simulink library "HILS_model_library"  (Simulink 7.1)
undefined symbols (not defined in the file or in its folder): hilsmdl
libraries: simulink x47, simulink_extras x9, HILS_model_library x3
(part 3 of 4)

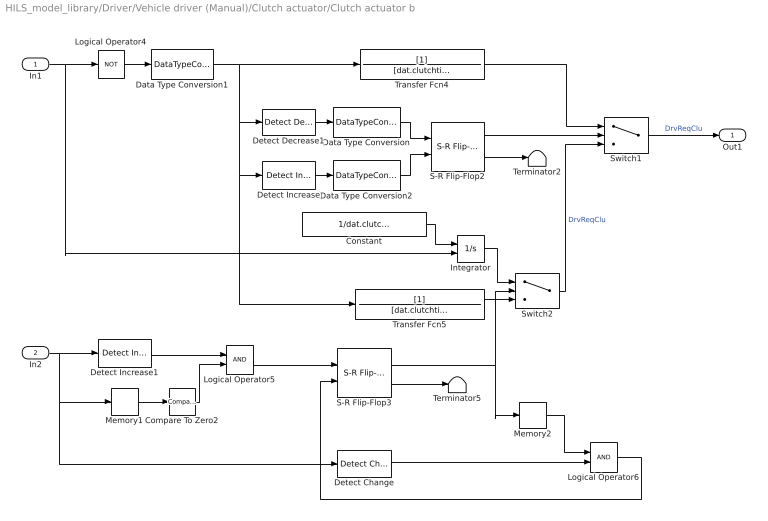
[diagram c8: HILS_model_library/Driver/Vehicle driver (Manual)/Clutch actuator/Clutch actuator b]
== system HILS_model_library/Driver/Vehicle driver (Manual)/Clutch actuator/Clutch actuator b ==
  In1 : Inport
  In2 : Inport  Port=2
  Compare To Zero2 : simulink/Logic and Bit Operations/Compare To Zero  SystemSampleTime=-1  relop===  LogicOutDataTypeMode=boolean
  Constant : Constant  Value=1/dat.clutchtime.driveaway.value
  Data Type Conversion : DataTypeConversion
  Data Type Conversion1 : DataTypeConversion
  Data Type Conversion2 : DataTypeConversion
  Detect Change : simulink/Logic and Bit Operations/Detect Change  SystemSampleTime=-1  vinit=0
  Detect Decrease1 : simulink/Logic and Bit Operations/Detect Decrease  SystemSampleTime=-1  vinit=0.0
  Detect Increase : simulink/Logic and Bit Operations/Detect Increase  SystemSampleTime=-1  vinit=0.0
  Detect Increase1 : simulink/Logic and Bit Operations/Detect Increase  SystemSampleTime=-1  vinit=0.0
  Integrator : Integrator  ExternalReset=either  LimitOutput=on  UpperSaturationLimit=1  LowerSaturationLimit=0
  Logical Operator4 : Logic  Operator=NOT  AllPortsSameDT=off  OutDataTypeMode=boolean  OutDataTypeStr=boolean
  Logical Operator5 : Logic  AllPortsSameDT=off  OutDataTypeMode=boolean  OutDataTypeStr=boolean
  Logical Operator6 : Logic  AllPortsSameDT=off  OutDataTypeMode=boolean  OutDataTypeStr=boolean
  Memory1 : Memory
  Memory2 : Memory
  S-R Flip-Flop2 : simulink_extras/Flip Flops/S-R Flip-Flop  SystemSampleTime=-1  initial_condition=0
  S-R Flip-Flop3 : simulink_extras/Flip Flops/S-R Flip-Flop  SystemSampleTime=-1  initial_condition=0
  Switch1 : Switch  Threshold=1
  Switch2 : Switch  Threshold=1
  Terminator2 : Terminator
  Terminator5 : Terminator
  Transfer Fcn4 : TransferFcn  Denominator=[dat.clutchtime.open.value 1]
  Transfer Fcn5 : TransferFcn  Denominator=[dat.clutchtime.close.value 1]
  Out1 : Outport
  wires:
  Constant/1 -> Integrator/1
  In2/1 -> Memory1/1, Detect Change/1, Detect Increase1/1
  Data Type Conversion1/1 -> Transfer Fcn5/1, Detect Increase/1, Detect Decrease1/1, Transfer Fcn4/1
  Detect Increase/1 -> Data Type Conversion2/1
  Switch1/1 -> Out1/1  "DrvReqClu"
  Transfer Fcn4/1 -> Switch1/1
  In1/1 -> Logical Operator4/1, Integrator/2
  Logical Operator4/1 -> Data Type Conversion1/1
  Detect Decrease1/1 -> Data Type Conversion/1
  Transfer Fcn5/1 -> Switch2/3
  S-R Flip-Flop3/2 -> Terminator5/1
  S-R Flip-Flop3/1 -> Memory2/1, Switch2/2
  Switch2/1 -> Switch1/3  "DrvReqClu"
  S-R Flip-Flop2/1 -> Switch1/2
  S-R Flip-Flop2/2 -> Terminator2/1
  Integrator/1 -> Switch2/1
  Logical Operator5/1 -> S-R Flip-Flop3/1
  Logical Operator6/1 -> S-R Flip-Flop3/2
  Memory2/1 -> Logical Operator6/1
  Detect Increase1/1 -> Logical Operator5/1
  Detect Change/1 -> Logical Operator6/2
  Compare To Zero2/1 -> Logical Operator5/2
  Memory1/1 -> Compare To Zero2/1
  Data Type Conversion/1 -> S-R Flip-Flop2/1
  Data Type Conversion2/1 -> S-R Flip-Flop2/2

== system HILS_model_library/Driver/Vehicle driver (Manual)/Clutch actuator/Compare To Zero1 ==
  u : Inport
  Compare : RelationalOperator  Operator===  LogicOutDataTypeMode=Specify via dialog  LogicDataType=fixdt(0, 8)  OutDataTypeStr=fixdt(0, 8)
  Ground : Ground  DisableCoverage=on
  Signal Specification : SignalSpecification  DisableCoverage=on  Dimensions=1
  y : Outport
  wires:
  Compare/1 -> y/1
  Ground/1 -> Signal Specification/1
  u/1 -> Compare/1
  Signal Specification/1 -> Compare/2

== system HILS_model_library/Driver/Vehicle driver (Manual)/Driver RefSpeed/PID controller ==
  PI reset : Inport
  PI input : Inport  Port=2
  Add : Sum  Inputs=+++
  Derivative : Derivative
  Integrator : Integrator  ExternalReset=rising  UpperSaturationLimit=30  LowerSaturationLimit=0
  Kd : Gain  Gain=dat.controller.d.value
  Ki : Gain  Gain=dat.controller.i.value
  Kp : Gain  Gain=dat.controller.p.value
  Kw : Gain  Orientation=left  Gain=dat.controller.k.value
  Saturation : Saturate  UpperLimit=1  LowerLimit=-1
  Sum1 : Sum  Inputs=|++
  Sum2 : Sum  Orientation=left  Inputs=-+|
  PI output : Outport
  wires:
  Derivative/1 -> Add/2
  Kd/1 -> Derivative/1
  PI input/1 -> Kd/1, Kp/1, Ki/1
  Integrator/1 -> Add/3
  Add/1 -> Saturation/1, Sum2/1
  Saturation/1 -> PI output/1, Sum2/2
  PI reset/1 -> Integrator/2
  Kp/1 -> Add/1
  Ki/1 -> Sum1/1
  Sum1/1 -> Integrator/1
  Sum2/1 -> Kw/1
  Kw/1 -> Sum1/2

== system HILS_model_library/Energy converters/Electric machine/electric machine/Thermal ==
  Total power loss : Inport
  Massflow cooling fluid : Inport  Port=2
  Bus Creator2 : BusCreator  Inputs=2
  Cooling2 : Subsystem
  c2 : Constant  Value=dat.coolingFluid.flowTemp.value
  Machine temperature[K] : Outport
  Fluid outlet temperature[K] : Outport  Port=2
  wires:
  Bus Creator2/1 -> Cooling2/2(cooling inlet)
  c2/1 -> Bus Creator2/2  "temperature [K]"
  Massflow cooling fluid/1 -> Bus Creator2/1  "mass flow [kg/s]"
  Cooling2/1(internal temperature) -> Machine temperature[K]/1  "ElecMac_tAct_K"
  Total power loss/1 -> Cooling2/1(power loss)
  Cooling2/2(fluid outlet temperature) -> Fluid outlet temperature[K]/1  "ElecMac_tActCoolingOut_K"

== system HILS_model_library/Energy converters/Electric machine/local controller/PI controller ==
  RefSpeed : Inport
  ActSpeed : Inport  Port=2
  Reset : Inport  Port=3
  Gain : Gain  Gain=dat.controller.i.value
  Gain2 : Gain  Gain=dat.controller.p.value
  Integrator : Integrator  ExternalReset=either
  Product : Product
  Sum : Sum  Inputs=|+-
  Sum1 : Sum  Inputs=|++
  Ctrl signal : Outport
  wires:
  Sum1/1 -> Ctrl signal/1
  Reset/1 -> Integrator/2, Product/2
  ActSpeed/1 -> Sum/2
  RefSpeed/1 -> Sum/1
  Product/1 -> Integrator/1
  Gain/1 -> Product/1
  Gain2/1 -> Sum1/2
  Integrator/1 -> Sum1/1
  Sum/1 -> Gain2/1, Gain/1

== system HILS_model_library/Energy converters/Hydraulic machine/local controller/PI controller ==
  Ref : Inport
  Act : Inport  Port=2
  Reset : Inport  Port=3
  Gain : Gain  Gain=dat.controller.i.value
  Gain2 : Gain  Gain=dat.controller.p.value
  Integrator : Integrator  ExternalReset=either
  Sum : Sum  Inputs=|+-
  Sum1 : Sum  Inputs=|++
  Ctrl signal : Outport
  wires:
  Sum/1 -> Gain/1, Gain2/1
  Integrator/1 -> Sum1/1
  Gain2/1 -> Sum1/2
  Gain/1 -> Integrator/1
  Ref/1 -> Sum/1
  Act/1 -> Sum/2
  Reset/1 -> Integrator/2
  Sum1/1 -> Ctrl signal/1

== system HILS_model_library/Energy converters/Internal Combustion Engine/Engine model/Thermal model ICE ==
  Torque ICE : Inport
  Eng speed : Inport  Port=2
  Calc ICE mech. Power : Product
  Compare To fixed temp (1=true) : simulink/Logic and Bit Operations/Compare To Constant  SystemSampleTime=-1  relop=>=  const=dat.cf.fixtemp.value-0.5  LogicOutDataTypeMode=uint8
  Compare To fixed temp (1=true)1 : simulink/Logic and Bit Operations/Compare To Constant  SystemSampleTime=-1  relop=>=  const=dat.oil.fixtemp.value-0.5  LogicOutDataTypeMode=uint8
  Constant : Constant  Value=0
  Integrator1 : Integrator
  Memory : Memory  X0=hilsmdl.init.temp.value
  Memory1 : Memory  X0=hilsmdl.init.temp.value
  MinMax : MinMax  Function=max  Inputs=2
  Switch : Switch  Criteria=u2 > Threshold
  Switch1 : Switch  Criteria=u2 > Threshold
  cooling fluid map : Lookup  InputValues=dat.cf.heatloss.vec  Table=dat.cf.temp.vec  LookUpMeth=Interpolation-Use End Values
  energy loss to cooling and oil [kJ] : Gain  Gain=1/1000
  fixed temp : Constant  Value=dat.cf.fixtemp.value
  fixed temp1 : Constant  Value=dat.oil.fixtemp.value
  oil map : Lookup  InputValues=dat.oil.heatloss.vec  Table=dat.oil.temp.vec  LookUpMeth=Interpolation-Use End Values
  temperature cooling fluid [K] : Outport
  temperature oil [K] : Outport  Port=2
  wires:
  Eng speed/1 -> Calc ICE mech. Power/1
  Torque ICE/1 -> Calc ICE mech. Power/2
  Calc ICE mech. Power/1 -> MinMax/1  "mech. power ICE [W]"
  Integrator1/1 -> energy loss to cooling and oil [kJ]/1
  energy loss to cooling and oil [kJ]/1 -> cooling fluid map/1, oil map/1
  cooling fluid map/1 -> Switch/3
  Memory/1 -> Compare To fixed temp (1=true)/1
  Compare To fixed temp (1=true)/1 -> Switch/2
  fixed temp/1 -> Switch/1
  oil map/1 -> Switch1/3
  Memory1/1 -> Compare To fixed temp (1=true)1/1
  Compare To fixed temp (1=true)1/1 -> Switch1/2
  fixed temp1/1 -> Switch1/1
  Switch1/1 -> temperature oil [K]/1, Memory1/1
  Switch/1 -> temperature cooling fluid [K]/1, Memory/1
  MinMax/1 -> Integrator1/1
  Constant/1 -> MinMax/2

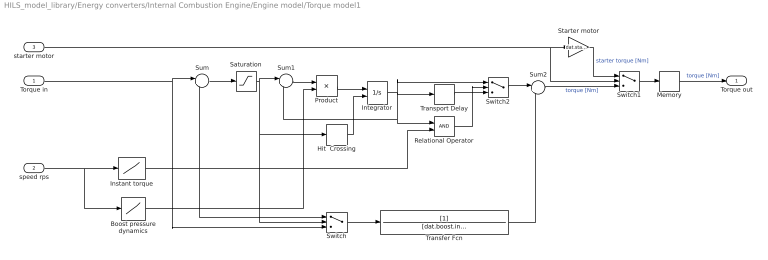
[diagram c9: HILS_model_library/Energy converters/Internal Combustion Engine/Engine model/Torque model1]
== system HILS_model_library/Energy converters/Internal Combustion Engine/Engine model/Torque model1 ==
  Torque in : Inport
  speed rps : Inport  Port=2
  starter motor : Inport  Port=3
  Boost pressure dynamics : Lookup  InputValues=dat.boost.speed.vec  Table=dat.boost.timeconstant.T2.vec  LookUpMeth=Interpolation-Use End Values
  Hit  Crossing : HitCross  HitCrossingDirection=falling
  Instant torque : Lookup  InputValues=dat.boost.speed.vec  Table=dat.boost.insttorque.vec  LookUpMeth=Interpolation-Use End Values
  Integrator : Integrator  ExternalReset=rising
  Memory : Memory
  Product : Product  Inputs=*/
  Relational Operator : RelationalOperator  LogicOutDataTypeMode=boolean  OutDataTypeStr=boolean
  Saturation : Saturate  UpperLimit=inf  LowerLimit=0
  Starter motor : Gain  Gain=dat.startertorque.value
  Sum : Sum  Inputs=|+-
  Sum1 : Sum  Inputs=|+-
  Sum2 : Sum  Inputs=|++
  Switch : Switch  Criteria=u2 > Threshold
  Switch1 : Switch  Threshold=0.5
  Switch2 : Switch  Criteria=u2 > Threshold  Threshold=0.5
  Transfer Fcn : TransferFcn  Denominator=[dat.boost.insttorque.timeconstant.T1.value/3 1]
  Transport Delay : TransportDelay  DelayTime=dat.boost.insttorque.timeconstant.T1.value
  Torque out : Outport
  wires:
  Starter motor/1 -> Switch1/1  "starter torque [Nm]"
  Sum2/1 -> Switch1/3  "torque [Nm]"
  Switch1/1 -> Memory/1
  starter motor/1 -> Starter motor/1, Switch1/2
  Memory/1 -> Torque out/1  "torque [Nm]"
  Hit  Crossing/1 -> Integrator/2
  Switch/1 -> Transfer Fcn/1
  Product/1 -> Integrator/1
  Sum1/1 -> Product/1
  Saturation/1 -> Switch/2, Hit  Crossing/1, Sum1/1
  Torque in/1 -> Switch/3, Sum/1
  Sum/1 -> Saturation/1
  Instant torque/1 -> Switch/1, Relational Operator/2, Sum/2
  Boost pressure dynamics/1 -> Product/2
  speed rps/1 -> Boost pressure dynamics/1, Instant torque/1
  Transfer Fcn/1 -> Sum2/2
  Integrator/1 -> Switch2/1, Transport Delay/1, Relational Operator/1, Sum1/2
  Relational Operator/1 -> Switch2/2
  Transport Delay/1 -> Switch2/3
  Switch2/1 -> Sum2/1

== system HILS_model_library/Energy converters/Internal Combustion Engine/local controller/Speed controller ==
  RefSpeed : Inport
  ActSpeed : Inport  Orientation=up  Port=2
  Reset : Inport  Orientation=up  Port=3
  Gain : Gain  Gain=dat.controller.i.value
  Gain2 : Gain  Gain=dat.controller.p.value
  Integrator : Integrator  ExternalReset=either
  Product : Product
  Saturation : Saturate  UpperLimit=max(dat.maxtorque.torque.vec)-min(dat.friction.friction.vec)  LowerLimit=0
  Sum : Sum  Inputs=|+-
  Sum1 : Sum  Inputs=|++
  ctrl signal : Outport
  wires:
  Sum/1 -> Gain/1, Gain2/1
  Integrator/1 -> Sum1/1
  Gain2/1 -> Sum1/2
  Gain/1 -> Product/1
  Product/1 -> Integrator/1
  ActSpeed/1 -> Sum/2
  Reset/1 -> Product/2, Integrator/2
  RefSpeed/1 -> Sum/1
  Sum1/1 -> Saturation/1
  Saturation/1 -> ctrl signal/1

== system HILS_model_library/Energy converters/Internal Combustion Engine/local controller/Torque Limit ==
  TorqueDemand : Inport
  ActSpeed : Inport  Port=2
  Constant1 : Constant  Value=0
  Friction map : Lookup  InputValues=dat.friction.speed.vec  Table=dat.friction.friction.vec  LookUpMeth=Interpolation-Use End Values
  Max Torque : Lookup  InputValues=dat.maxtorque.speed.vec  Table=dat.maxtorque.torque.vec  LookUpMeth=Interpolation-Use End Values
  Saturation Dynamic : simulink/Discontinuities/Saturation Dynamic  SystemSampleTime=-1  OutMin=[]  OutMax=[]  OutDataTypeStr=Inherit: Same as second input  OutDataType=fixdt(1, 16)  OutScaling=2^-10  DoSatur=off
  Sum : Sum  Inputs=+-
  LimitTorqueDemand : Outport
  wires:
  Constant1/1 -> Saturation Dynamic/3
  ActSpeed/1 -> Max Torque/1, Friction map/1
  TorqueDemand/1 -> Saturation Dynamic/2
  Saturation Dynamic/1 -> LimitTorqueDemand/1  "Eng_tqIndReq_Nm"
  Friction map/1 -> Sum/2
  Max Torque/1 -> Sum/1
  Sum/1 -> Saturation Dynamic/1

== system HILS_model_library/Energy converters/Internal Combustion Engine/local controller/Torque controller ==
  RefTorque : Inport
  ActSpeed : Inport  Port=2
  Friction map : Lookup  InputValues=dat.friction.speed.vec  Table=dat.friction.friction.vec  LookUpMeth=Interpolation-Use End Values
  Product1 : Product
  Sum2 : Sum  Inputs=+-
  Torque req  Indicated torque = 0 Crankshaft torque = 1 : Constant  Value=dat.torquereqtype.value
  TotalTorqueRef : Outport
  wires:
  Friction map/1 -> Product1/2
  RefTorque/1 -> Sum2/1
  ActSpeed/1 -> Friction map/1
  Sum2/1 -> TotalTorqueRef/1
  Product1/1 -> Sum2/2
  Torque req  Indicated torque = 0 Crankshaft torque = 1/1 -> Product1/1

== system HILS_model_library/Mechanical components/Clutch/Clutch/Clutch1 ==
  T_reqClu : Inport
  T_in : Inport  Port=2
  J_in : Inport  Port=3
  w_down : Inport  Port=4
  Maxtorque : Inport  Port=5
  Clutch mode : Subsystem
  Demux : Demux  Outputs=3
  Locked clutch : Subsystem
  Memory1 : Memory
  Memory2 : Memory  Orientation=left
  Mux : Mux  Inputs=3
  Mux1 : Mux  Inputs=3
  Slipping clutch : Subsystem  TreatAsAtomicUnit=on
  Switch : Switch  Criteria=u2 ~= 0
  T_out : Outport
  J_out : Outport  Port=2
  w_up : Outport  Port=3
  B_cluLock : Outport  Port=4
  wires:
  Maxtorque/1 -> Slipping clutch/6(Maxtorque)
  Memory1/1 -> Locked clutch/3(w_down), Slipping clutch/3(w_down), Clutch mode/1(w_down)
  Memory2/1 -> Clutch mode/3(w_internal)
  T_in/1 -> Locked clutch/1(T_in), Slipping clutch/1(T_in)
  T_reqClu/1 -> Slipping clutch/4(T_reqClu), Clutch mode/2(T_reqClu)
  J_in/1 -> Locked clutch/2(J_in), Slipping clutch/2(J_in)
  w_down/1 -> Memory1/1
  Slipping clutch/1(T_out) -> Mux1/1
  Slipping clutch/2(J_out) -> Mux1/2
  Slipping clutch/3(w_up) -> Mux1/3
  Locked clutch/1(T_out) -> Mux/1
  Locked clutch/2(J_out) -> Mux/2
  Locked clutch/3(w_up) -> Mux/3
  Mux1/1 -> Switch/1
  Mux/1 -> Switch/3
  Clutch mode/1(B_cluLock) -> B_cluLock/1
  Switch/1 -> Demux/1
  Clutch mode/2(B_cluSlip) -> Slipping clutch/5(B_cluSlip), Switch/2
  Demux/3 -> w_up/1, Memory2/1
  Demux/1 -> T_out/1
  Demux/2 -> J_out/1

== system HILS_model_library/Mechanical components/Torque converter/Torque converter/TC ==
  T_reqClu : Inport
  J_in : Inport  Port=2
  T_in : Inport  Port=3
  w_down : Inport  Port=4
  Bus Creator : BusCreator  Inputs=6
  Bus Creator1 : BusCreator  Inputs=6
  Bus Selector : BusSelector  OutputSignals=phys_torque_Nm,phys_inertia_kgm2,phys_speed_radps,TC_tqTurbineAct_Nm,TC_nTurbineAct_radps,TC_tqPumpAct_Nm
  Memory : Memory
  Memory1 : Memory  Orientation=left
  Switch1 : Switch  Threshold=1
  TC mode : Subsystem
  Terminator : Terminator
  lockUp_mode : Subsystem
  operating_mode : Subsystem
  T_out : Outport
  J_out : Outport  Port=2
  w_out : Outport  Port=3
  sens1 : Outport  Port=4
  sens2 : Outport  Port=5
  sens3 : Outport  Port=6
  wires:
  Switch1/1 -> Bus Selector/1
  TC mode/2(B_TcSlip) -> Terminator/1
  TC mode/1(B_TcLock) -> Switch1/2
  Memory/1 -> lockUp_mode/3(w_down), TC mode/1(w_down), operating_mode/4(w_down)
  w_down/1 -> Memory/1
  T_in/1 -> operating_mode/3(T_in), lockUp_mode/2(T_in)
  Bus Creator1/1 -> Switch1/3
  Bus Selector/6 -> sens3/1  "<TC_tqPumpAct_Nm>"
  Bus Selector/5 -> sens2/1  "<TC_nTurbineAct_radps>"
  Bus Selector/4 -> sens1/1  "<TC_tqTurbineAct_Nm>"
  Bus Selector/3 -> w_out/1, Memory1/1  "<phys_speed_radps>"
  T_reqClu/1 -> operating_mode/1(T_reqClu), TC mode/2(T_reqClu)
  Bus Selector/2 -> J_out/1  "<phys_inertia_kgm2>"
  Bus Selector/1 -> T_out/1  "<phys_torque_Nm>"
  lockUp_mode/6(sens3) -> Bus Creator/6
  lockUp_mode/5(sens2) -> Bus Creator/5
  lockUp_mode/4(sens1) -> Bus Creator/4
  operating_mode/6(sens3) -> Bus Creator1/6
  operating_mode/5(sens2) -> Bus Creator1/5
  operating_mode/4(sens1) -> Bus Creator1/4
  operating_mode/3(w_up) -> Bus Creator1/3
  operating_mode/2(J_out) -> Bus Creator1/2
  operating_mode/1(T_out) -> Bus Creator1/1
  Bus Creator/1 -> Switch1/1
  J_in/1 -> lockUp_mode/1(J_in), operating_mode/2(J_in)
  lockUp_mode/3(w_up) -> Bus Creator/3
  lockUp_mode/1(T_out) -> Bus Creator/1
  lockUp_mode/2(J_out) -> Bus Creator/2
  Memory1/1 -> TC mode/3(w_internal)

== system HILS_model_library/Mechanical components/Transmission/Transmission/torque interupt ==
  clutch : Inport
  torque : Inport  Port=2
  inertia : Inport  Port=3
  speed : Inport  Port=4
  " transmission max  torque [Nm]" : Constant  Value=dat.maxtorque.value
  Product : Product
  Saturation : Saturate  UpperLimit=1  LowerLimit=0
  actuator : Subsystem
  torque1 : Outport
  inertia1 : Outport  Port=2
  speed1 : Outport  Port=3
  B_cluLock : Outport  Port=4
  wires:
  actuator/4(B_cluLock) -> B_cluLock/1
  Product/1 -> actuator/1(T_reqClu)
  Saturation/1 -> Product/1
  " transmission max  torque [Nm]"/1 -> Product/2
  speed/1 -> actuator/4(w_down)
  inertia/1 -> actuator/3(J_in)
  torque/1 -> actuator/2(T_in)
  actuator/3(w_up) -> speed1/1  "phys_speed_radps"
  actuator/2(J_out) -> inertia1/1  "phys_inertia_kgm2"
  actuator/1(T_out) -> torque1/1  "phys_torque_Nm"
  clutch/1 -> Saturation/1

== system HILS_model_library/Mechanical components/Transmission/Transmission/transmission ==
  gear : Inport
  torque : Inport  Port=2
  inertia : Inport  Port=3
  speed : Inport  Port=4
  "0 -> nog" : Saturate  UpperLimit=dat.nofgear.value+1  LowerLimit=0
  Abs : Abs
  Constant1 : Constant  Value=0
  Fcn2 : Fcn  Expr=1/u(1)
  Memory : Memory  Orientation=left
  Sum : Sum
  Switch3 : Switch
  Switch4 : Switch  Criteria=u2 ~= 0
  gear ratio : Lookup  InputValues=dat.gear.number.vec  Table=dat.gear.ratio.vec  LookUpMeth=Interpolation-Use End Values
  inertia ratio : Product  Inputs=3
  inertia=f(gear) : Lookup  InputValues=dat.gear.number.vec  Table=dat.gear.inertia.vec  LookUpMeth=Interpolation-Use End Values
  n-D Lookup Table : Lookup_n-D  NumberOfTableDimensions=3  BreakpointsForDimension1=dat.gear.number.vec  BreakpointsForDimension2=dat.gear.mechefficiency.torque.vec  BreakpointsForDimension3=dat.gear.mechefficiency.speed.vec  Table=dat.gear.mechefficiency.efficiency.map  ExtrapMethod=None - Clip  UseLastTableValue=on
  speed ratio : Product
  torque ratio : Product  Inputs=3
  torque1 : Outport
  inertia1 : Outport  Port=2
  speed1 : Outport  Port=3
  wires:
  speed ratio/1 -> Memory/1, speed1/1  "phys_speed_radps"
  speed/1 -> speed ratio/1
  inertia ratio/1 -> inertia1/1  "phys_inertia_kgm2"
  inertia/1 -> Sum/1
  torque ratio/1 -> torque1/1  "phys_torque_Nm"
  gear/1 -> "0 -> nog"/1
  gear ratio/1 -> torque ratio/1, speed ratio/2, inertia ratio/2, inertia ratio/1
  Sum/1 -> inertia ratio/3
  inertia=f(gear)/1 -> Sum/2
  "0 -> nog"/1 -> inertia=f(gear)/1, n-D Lookup Table/1, Switch4/2, gear ratio/1
  Abs/1 -> n-D Lookup Table/2
  torque/1 -> Abs/1, Switch3/2, torque ratio/2
  n-D Lookup Table/1 -> Switch3/1, Fcn2/1  "efficiency"
  Switch3/1 -> Switch4/1
  Fcn2/1 -> Switch3/3
  Constant1/1 -> Switch4/3
  Switch4/1 -> torque ratio/3
  Memory/1 -> n-D Lookup Table/3

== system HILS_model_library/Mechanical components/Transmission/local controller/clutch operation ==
  Gear : Inport
  Compare To Zero : simulink/Logic and Bit Operations/Compare To Zero  SystemSampleTime=-1  relop=>  LogicOutDataTypeMode=uint8
  Const1 : Constant
  Data Type Conversion4 : DataTypeConversion
  Logical Operator1 : Logic  AllPortsSameDT=off  OutDataTypeMode=boolean  OutDataTypeStr=boolean
  Logical Operator2 : Logic  AllPortsSameDT=off  OutDataTypeMode=boolean  OutDataTypeStr=boolean
  Relational Operator : RelationalOperator  Operator===  LogicOutDataTypeMode=boolean  OutDataTypeStr=boolean
  Transport Delay : TransportDelay  DelayTime=dat.timetrqinterrupt.value  BufferSize=4096
  Clutchctrl : Outport
  Actual Gear : Outport  Port=2
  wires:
  Compare To Zero/1 -> Logical Operator2/2
  Data Type Conversion4/1 -> Clutchctrl/1
  Logical Operator2/1 -> Data Type Conversion4/1
  Const1/1 -> Logical Operator1/1
  Logical Operator1/1 -> Logical Operator2/1
  Relational Operator/1 -> Logical Operator1/2
  Transport Delay/1 -> Relational Operator/2, Actual Gear/1, Compare To Zero/1  "Transm_nrGearAct"
  Gear/1 -> Transport Delay/1, Relational Operator/1

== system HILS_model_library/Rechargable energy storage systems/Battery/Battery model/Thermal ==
  Total power loss : Inport
  Massflow cooling fluid : Inport  Port=2
  Bus Creator2 : BusCreator  Inputs=2
  Cooling2 : Subsystem
  c2 : Constant  Value=dat.coolingFluid.flowTemp.value
  Storage temperature[K] : Outport
  Fluid outlet temperature[K] : Outport  Port=2
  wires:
  Bus Creator2/1 -> Cooling2/2(cooling inlet)
  c2/1 -> Bus Creator2/2  "temperature [K]"
  Massflow cooling fluid/1 -> Bus Creator2/1  "mass flow [kg/s]"
  Cooling2/1(internal temperature) -> Storage temperature[K]/1  "Batt_tAct_K"
  Total power loss/1 -> Cooling2/1(power loss)
  Cooling2/2(fluid outlet temperature) -> Fluid outlet temperature[K]/1  "Batt_tActCoolingOut_K"

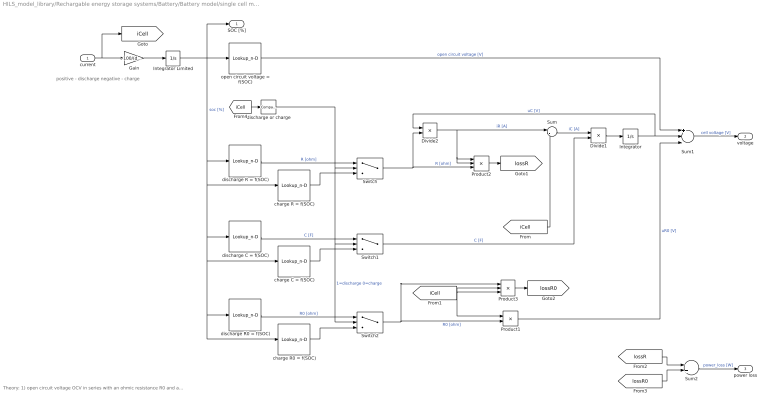
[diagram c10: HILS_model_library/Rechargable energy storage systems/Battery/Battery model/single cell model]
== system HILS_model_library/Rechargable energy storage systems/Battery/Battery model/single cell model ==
  note: Theory: 1) open circuit voltage OCV in series with an ohmic resistance R0 and a R-C parallel circuit 2) all parameters depend on SOC 3) power loss is due to loss in R0 and R
  note: positive - discharge negative - charge
  current : Inport
  Divide1 : Product  Inputs=*/
  Divide2 : Product  Inputs=*/
  Gain : Gain  Gain=-100/(dat.capacity.value*3600)
  Integrator : Integrator
  Integrator Limited : Integrator  InitialCondition=dat.initialSOC.value  LimitOutput=on  UpperSaturationLimit=100  LowerSaturationLimit=0
  Product1 : Product  Inputs=**
  Product2 : Product  Inputs=***
  Product3 : Product  Inputs=***
  Sum : Sum  Inputs=|-+
  Sum1 : Sum  Inputs=+--
  Sum2 : Sum
  Switch : Switch  Criteria=u2 > Threshold  Threshold=0.5
  Switch1 : Switch  Criteria=u2 > Threshold  Threshold=0.5
  Switch2 : Switch  Criteria=u2 > Threshold  Threshold=0.5
  charge C = f(SOC) : Lookup_n-D  NumberOfTableDimensions=1  BreakpointsForDimension1=dat.resi.charge.soc.vec  BeginIndexSearchUsingPreviousIndexResult=on  Table=dat.resi.charge.C.vec  ExtrapMethod=None - Clip  UseLastTableValue=on
  charge R = f(SOC) : Lookup_n-D  NumberOfTableDimensions=1  BreakpointsForDimension1=dat.resi.charge.soc.vec  BeginIndexSearchUsingPreviousIndexResult=on  Table=dat.resi.charge.R.vec  ExtrapMethod=None - Clip  UseLastTableValue=on
  charge R0 = f(SOC) : Lookup_n-D  NumberOfTableDimensions=1  BreakpointsForDimension1=dat.resi.charge.soc.vec  BeginIndexSearchUsingPreviousIndexResult=on  Table=dat.resi.charge.R0.vec  ExtrapMethod=None - Clip  UseLastTableValue=on
  discharge or charge : simulink/Logic and Bit Operations/Compare To Constant  SystemSampleTime=-1  relop=>=  const=0  LogicOutDataTypeMode=uint8
  discharge C = f(SOC) : Lookup_n-D  NumberOfTableDimensions=1  BreakpointsForDimension1=dat.resi.discharge.soc.vec  BeginIndexSearchUsingPreviousIndexResult=on  Table=dat.resi.discharge.C.vec  ExtrapMethod=None - Clip  UseLastTableValue=on
  discharge R = f(SOC) : Lookup_n-D  NumberOfTableDimensions=1  BreakpointsForDimension1=dat.resi.discharge.soc.vec  BeginIndexSearchUsingPreviousIndexResult=on  Table=dat.resi.discharge.R.vec  ExtrapMethod=None - Clip  UseLastTableValue=on
  discharge R0 = f(SOC) : Lookup_n-D  NumberOfTableDimensions=1  BreakpointsForDimension1=dat.resi.discharge.soc.vec  BeginIndexSearchUsingPreviousIndexResult=on  Table=dat.resi.discharge.R0.vec  ExtrapMethod=None - Clip  UseLastTableValue=on
  open circuit voltage = f(SOC) : Lookup_n-D  NumberOfTableDimensions=1  BreakpointsForDimension1=dat.ocv.soc.vec  BeginIndexSearchUsingPreviousIndexResult=on  Table=dat.ocv.ocv.vec  ExtrapMethod=None - Clip  UseLastTableValue=on
  SOC [%] : Outport
  voltage : Outport  Port=2
  power loss : Outport  Port=3
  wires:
  Gain/1 -> Integrator Limited/1
  Sum2/1 -> power loss/1  "power_loss [W]"
  Sum1/1 -> voltage/1  "cell voltage [V]"
  [lossR] -> Sum2/1
  [lossR0] -> Sum2/2
  Product3/1 -> [lossR0]
  Product2/1 -> [lossR]
  Product1/1 -> Sum1/3  "uR0 [V]"
  [iCell] -> Product3/3, Product3/2, Product1/1
  Integrator/1 -> Sum1/2, Divide2/1  "uC [V]"
  Divide1/1 -> Integrator/1
  Sum/1 -> Divide1/1  "iC [A]"
  [iCell] -> Sum/2
  Divide2/1 -> Sum/1, Product2/1, Product2/2  "iR [A]"
  open circuit voltage = f(SOC)/1 -> Sum1/1  "open circuit voltage [V]"
  current/1 -> [iCell], Gain/1
  [iCell] -> discharge or charge/1
  Switch/1 -> Divide2/2, Product2/3  "R [ohm]"
  discharge or charge/1 -> Switch2/2, Switch1/2, Switch/2  "1=discharge 0=charge"
  discharge R = f(SOC)/1 -> Switch/1  "R [ohm]"
  charge R = f(SOC)/1 -> Switch/3
  Switch1/1 -> Divide1/2  "C [F]"
  discharge C = f(SOC)/1 -> Switch1/1  "C [F]"
  charge C = f(SOC)/1 -> Switch1/3
  Switch2/1 -> Product3/1, Product1/2  "R0 [ohm]"
  discharge R0 = f(SOC)/1 -> Switch2/1  "R0 [ohm]"
  charge R0 = f(SOC)/1 -> Switch2/3
  Integrator Limited/1 -> open circuit voltage = f(SOC)/1, SOC [%]/1, discharge R = f(SOC)/1, charge R = f(SOC)/1, discharge C = f(SOC)/1, charge C = f(SOC)/1, discharge R0 = f(SOC)/1, charge R0 = f(SOC)/1  "soc [%]"

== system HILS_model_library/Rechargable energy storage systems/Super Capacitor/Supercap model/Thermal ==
  Total power loss : Inport
  Massflow cooling fluid : Inport  Port=2
  Bus Creator2 : BusCreator  Inputs=2
  Cooling2 : HILS_model_library/Rechargable energy storage systems/Battery/Battery model/Thermal/Cooling2  SystemSampleTime=-1
  c2 : Constant  Value=dat.coolingFluid.flowTemp.value
  Storage temperature[K] : Outport
  Fluid outlet temperature[K] : Outport  Port=2
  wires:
  Bus Creator2/1 -> Cooling2/2
  c2/1 -> Bus Creator2/2  "temperature [K]"
  Massflow cooling fluid/1 -> Bus Creator2/1  "mass flow [kg/s]"
  Cooling2/1 -> Storage temperature[K]/1  "Capa_tAct_K"
  Total power loss/1 -> Cooling2/1
  Cooling2/2 -> Fluid outlet temperature[K]/1  "Capa_tActCoolingOut_K"

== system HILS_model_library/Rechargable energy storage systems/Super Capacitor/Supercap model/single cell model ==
  note: positive - discharge negative - charge
  note: Theory: Supercap modelled as capacitor C in series with the internal resistance R
  current : Inport
  1-D Lookup Table : Lookup_n-D  NumberOfTableDimensions=1  BreakpointsForDimension1=[dat.Vmin.value dat.Vmax.value]  Table=[0 100]  ExtrapMethod=None - Clip  UseLastTableValue=on
  Gain : Gain  Gain=-1/dat.C.value
  Gain1 : Gain  Gain=-dat.R.value
  Gain2 : Gain  Gain=dat.R.value
  Integrator Limited : Integrator  InitialCondition=dat.initialVoltage.value  LimitOutput=on  UpperSaturationLimit=dat.Vmax.value  LowerSaturationLimit=dat.Vmin.value
  Product : Product
  Sum3 : Sum
  SOC [%] : Outport
  voltage : Outport  Port=2
  power loss : Outport  Port=3
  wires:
  1-D Lookup Table/1 -> SOC [%]/1
  Product/1 -> Gain2/1
  Gain1/1 -> Sum3/2  "ohmic voltage drop [V]"
  Integrator Limited/1 -> 1-D Lookup Table/1, Sum3/1  "V_internal [V]"
  Gain/1 -> Integrator Limited/1
  current/1 -> Product/2, Product/1, Gain1/1, Gain/1
  Sum3/1 -> voltage/1  "cell voltage [V]"
  Gain2/1 -> power loss/1  "power_loss [W]"

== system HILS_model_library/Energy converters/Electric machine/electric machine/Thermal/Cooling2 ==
  power loss : Inport
  cooling inlet : Inport  Port=2
  Add1 : Sum  Inputs=-+
  Add2 : Sum  Inputs=-+
  Bus Selector : BusSelector  OutputSignals=mass flow [kg/s],temperature [K]
  Gain : Gain  Gain=1/dat.Rth.value
  Gain1 : Gain  Gain=1/dat.cm.value
  Integrator : Integrator  InitialCondition=hilsmdl.init.temp.value
  Mux : Mux  Inputs=3
  Mux1 : Mux  Inputs=2
  calc mean temperature : Fcn  Expr=dat.alpha.value*u(1) + (1-dat.alpha.value)*u(2)
  calc outlet temperature : Fcn  Expr=(u(3)+u(2)*(dat.Rth.value*dat.coolingFluid.c.value*u(1)-dat.alpha.value)) / (1+dat.Rth.value*dat.coolingFluid.c.value*u(1)-dat.alpha.value)
  internal temperature : Outport
  fluid outlet temperature : Outport  Port=2
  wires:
  Mux/1 -> calc outlet temperature/1
  calc outlet temperature/1 -> Mux1/2, fluid outlet temperature/1  "fluid outlet temperature [K]"
  Bus Selector/2 -> Mux1/1, Mux/2  "<temperature [K]>"
  Add1/1 -> Gain/1
  Gain/1 -> Add2/1  "P cooling [W]"
  Add2/1 -> Gain1/1
  Gain1/1 -> Integrator/1
  Integrator/1 -> Mux/3, Add1/2, internal temperature/1  "internal temperature [K]"
  cooling inlet/1 -> Bus Selector/1
  power loss/1 -> Add2/2  "power loss [W]"
  Mux1/1 -> calc mean temperature/1
  calc mean temperature/1 -> Add1/1  "T_mean [K]"
  Bus Selector/1 -> Mux/1  "<mass flow [kg/s]>"

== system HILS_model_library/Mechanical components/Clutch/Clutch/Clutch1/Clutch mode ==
  w_down : Inport
  T_reqClu : Inport  Port=2
  w_internal : Inport  Port=3
  Abs : Abs
  Add : Sum  Inputs=+-
  Check request condition : RelationalOperator  LogicOutDataTypeMode=boolean  OutDataTypeStr=boolean
  Check request condition2 : RelationalOperator  Operator=<  LogicOutDataTypeMode=boolean  OutDataTypeStr=boolean
  Check speed condition : RelationalOperator  Operator=<  LogicOutDataTypeMode=boolean  OutDataTypeStr=boolean
  Clutch locked S-R Flip-Flop : simulink_extras/Flip Flops/S-R Flip-Flop  SystemSampleTime=-1  initial_condition=0
  Conditions for clutch lock : Logic  AllPortsSameDT=off  OutDataTypeMode=boolean  OutDataTypeStr=boolean
  Speed tolerance [rad/s] : Constant  Value=dat.speedtolerance.value
  clutch threshold : Constant  Value=dat.maxtorque.value*dat.clutchthreshold.value
  B_cluLock : Outport
  B_cluSlip : Outport  Port=2
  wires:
  w_down/1 -> Add/1
  Add/1 -> Abs/1
  w_internal/1 -> Add/2
  Abs/1 -> Check speed condition/1
  Speed tolerance [rad/s]/1 -> Check speed condition/2
  Check speed condition/1 -> Conditions for clutch lock/1  "speed_ok"
  T_reqClu/1 -> Check request condition/1, Check request condition2/1
  clutch threshold/1 -> Check request condition2/2, Check request condition/2
  Check request condition/1 -> Conditions for clutch lock/2  "req_ok"
  Conditions for clutch lock/1 -> Clutch locked S-R Flip-Flop/1  "set_lock"
  Check request condition2/1 -> Clutch locked S-R Flip-Flop/2  "req_to_low"
  Clutch locked S-R Flip-Flop/1 -> B_cluLock/1
  Clutch locked S-R Flip-Flop/2 -> B_cluSlip/1

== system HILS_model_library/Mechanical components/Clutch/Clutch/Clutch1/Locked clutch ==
  T_in : Inport
  J_in : Inport  Port=2
  w_down : Inport  Port=3
  Add1 : Sum  Inputs=+++
  Clutch inputside inertia [kgm^2] : Constant  Value=dat.in.inertia.value
  Clutch outputside inertia [kgm^2] : Constant  Value=dat.out.inertia.value
  Gain : Gain
  Gain1 : Gain
  T_out : Outport
  J_out : Outport  Port=2
  w_up : Outport  Port=3
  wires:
  w_down/1 -> Gain/1
  Gain/1 -> w_up/1
  T_in/1 -> Gain1/1
  Gain1/1 -> T_out/1
  Clutch inputside inertia [kgm^2]/1 -> Add1/2
  Clutch outputside inertia [kgm^2]/1 -> Add1/3
  J_in/1 -> Add1/1
  Add1/1 -> J_out/1

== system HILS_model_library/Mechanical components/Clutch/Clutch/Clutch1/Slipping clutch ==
  T_in : Inport
  J_in : Inport  Port=2
  w_down : Inport  Port=3
  T_reqClu : Inport  Port=4
  B_cluSlip : Inport  Port=5
  Maxtorque : Inport  Port=6
  0 when not slipping : Product  Inputs=**
  Abs : Abs
  Add1 : Sum  Inputs=+-
  Add2 : Sum  Inputs=+-
  Add3 : Sum
  Calculate input side acc : Product  Inputs=/*
  Clutch inputside inertia [kgm^2] : Constant  Value=dat.in.inertia.value
  Clutch outputside inertia [kgm^2] : Constant  Value=dat.out.inertia.value
  Fcn : Fcn  Orientation=left  Expr=tanh(dat.tanh.value*u(1))
  Integrate input side speed : Integrator  ExternalReset=rising  InitialConditionSource=external  LimitOutput=on  UpperSaturationLimit=1000  LowerSaturationLimit=0
  Limit to clutch maximum torque : MinMax  Inputs=2
  Torque direction : Product  Inputs=**
  T_out : Outport
  J_out : Outport  Port=2
  w_up : Outport  Port=3
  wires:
  Fcn/1 -> Torque direction/2
  Calculate input side acc/1 -> 0 when not slipping/1
  0 when not slipping/1 -> Integrate input side speed/1
  T_in/1 -> Add1/1
  T_reqClu/1 -> Abs/1
  Maxtorque/1 -> Limit to clutch maximum torque/2
  B_cluSlip/1 -> Integrate input side speed/2, 0 when not slipping/2
  w_down/1 -> Add2/2, Integrate input side speed/3
  Integrate input side speed/1 -> w_up/1, Add2/1
  Add1/1 -> Calculate input side acc/2  "acc torque"
  Limit to clutch maximum torque/1 -> Torque direction/1
  Abs/1 -> Limit to clutch maximum torque/1
  Torque direction/1 -> Add1/2, T_out/1
  Clutch outputside inertia [kgm^2]/1 -> J_out/1
  Add3/1 -> Calculate input side acc/1
  Clutch inputside inertia [kgm^2]/1 -> Add3/2
  J_in/1 -> Add3/1
  Add2/1 -> Fcn/1

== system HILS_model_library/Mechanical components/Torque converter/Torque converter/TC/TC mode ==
  w_down : Inport
  T_reqClu : Inport  Port=2
  w_internal : Inport  Port=3
  Abs : Abs
  Add : Sum  Inputs=+-
  Check request condition1 : RelationalOperator  LogicOutDataTypeMode=boolean  OutDataTypeStr=boolean
  Check request condition2 : RelationalOperator  Operator=<  LogicOutDataTypeMode=boolean  OutDataTypeStr=boolean
  Check speed condition : RelationalOperator  Operator=<  LogicOutDataTypeMode=boolean  OutDataTypeStr=boolean
  Clutch locked S-R Flip-Flop : simulink_extras/Flip Flops/S-R Flip-Flop  SystemSampleTime=-1  initial_condition=0
  Conditions for clutch lock : Logic  AllPortsSameDT=off  OutDataTypeMode=boolean  OutDataTypeStr=boolean
  Speed tolerance [rad/s] : Constant  Value=dat.clutch.speedtolerance.value
  clutch threshold : Constant  Value=dat.clutch.maxtorque.value*dat.clutch.threshold.value
  B_TcLock : Outport
  B_TcSlip : Outport  Port=2
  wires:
  Check request condition1/1 -> Conditions for clutch lock/2
  Clutch locked S-R Flip-Flop/2 -> B_TcSlip/1
  Clutch locked S-R Flip-Flop/1 -> B_TcLock/1
  Check request condition2/1 -> Clutch locked S-R Flip-Flop/2  "req_to_low"
  Conditions for clutch lock/1 -> Clutch locked S-R Flip-Flop/1  "set_lock"
  clutch threshold/1 -> Check request condition1/2, Check request condition2/2
  T_reqClu/1 -> Check request condition1/1, Check request condition2/1
  Check speed condition/1 -> Conditions for clutch lock/1  "speed_ok"
  Speed tolerance [rad/s]/1 -> Check speed condition/2
  Abs/1 -> Check speed condition/1
  w_internal/1 -> Add/2
  Add/1 -> Abs/1
  w_down/1 -> Add/1

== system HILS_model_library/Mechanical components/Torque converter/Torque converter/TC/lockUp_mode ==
  J_in : Inport
  T_in : Inport  Port=2
  w_down : Inport  Port=3
  Add2 : Sum  Inputs=+++
  Add3 : Sum  Inputs=|++
  Constant5 : Constant  Value=dat.inertia.in.value
  Constant6 : Constant  Value=dat.inertia.out.value
  Gain{1..4} (4 alike) : Gain
  loss torque at reference speed = f(speed ratio) : Lookup_n-D  NumberOfTableDimensions=1  BreakpointsForDimension1=dat.characteristics.loss.speed.vec  Table=dat.characteristics.loss.torque.vec  ExtrapMethod=None - Clip  UseLastTableValue=on
  T_out : Outport
  J_out : Outport  Port=2
  w_up : Outport  Port=3
  sens1 : Outport  Port=4
  sens2 : Outport  Port=5
  sens3 : Outport  Port=6
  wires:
  Gain3/1 -> w_up/1  "phys_speed_radps"
  Gain4/1 -> sens3/1  "TC_tqPumpAct_Nm"
  Gain2/1 -> sens1/1  "TC_tqTurbineAct_Nm"
  T_in/1 -> Add3/1, Gain4/1  "Input side torque"
  Gain1/1 -> sens2/1  "TC_nTurbineAct_radps"
  w_down/1 -> loss torque at reference speed = f(speed ratio)/1, Gain3/1, Gain1/1  "TC_nPumpAct_radps"
  Add2/1 -> J_out/1  "phys_inertia_kgm2"
  Add3/1 -> T_out/1, Gain2/1  "phys_torque_Nm"
  loss torque at reference speed = f(speed ratio)/1 -> Add3/2
  Constant6/1 -> Add2/2
  Constant5/1 -> Add2/1
  J_in/1 -> Add2/3

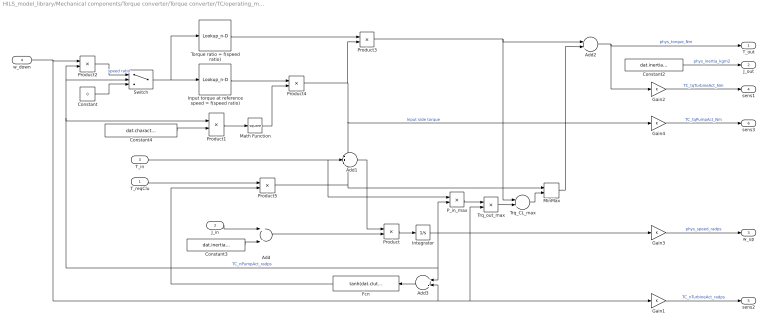
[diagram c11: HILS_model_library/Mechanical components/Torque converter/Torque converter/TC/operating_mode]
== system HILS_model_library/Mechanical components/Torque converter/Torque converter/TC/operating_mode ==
  T_reqClu : Inport
  J_in : Inport  Port=2
  T_in : Inport  Port=3
  w_down : Inport  Port=4
  Add : Sum
  Add1 : Sum  Inputs=-+-
  Add2 : Sum
  Add3 : Sum  Orientation=left  Inputs=+-
  Constant : Constant  Value=0
  Constant2 : Constant  Value=dat.inertia.out.value
  Constant3 : Constant  Value=dat.inertia.in.value
  Constant4 : Constant  Value=dat.characteristics.refspeed.value
  Fcn : Fcn  Orientation=left  Expr=tanh(dat.clutch.tanh.value*u(1))
  Gain{1..4} (4 alike) : Gain
  Input torque at reference speed = f(speed ratio) : Lookup_n-D  NumberOfTableDimensions=1  BreakpointsForDimension1=dat.characteristics.speedratio.vec  Table=dat.characteristics.inputtorque.vec  ExtrapMethod=None - Clip  UseLastTableValue=on
  Integrator : Integrator
  Math Function : Math  Operator=square
  MinMax : MinMax  Inputs=2
  P_in_max : Product  Inputs=**
  Product : Product  Inputs=*/
  Product1 : Product  Inputs=*/
  Product2 : Product  Inputs=*/
  Product3 : Product  Inputs=**
  Product4 : Product  Inputs=**
  Product5 : Product
  Switch : Switch  Criteria=u2 > Threshold
  Torque ratio = f(speed ratio) : Lookup_n-D  NumberOfTableDimensions=1  BreakpointsForDimension1=dat.characteristics.speedratio.vec  Table=dat.characteristics.torqueratio.vec  ExtrapMethod=None - Clip  UseLastTableValue=on
  Trq_CL_max : Sum  Inputs=-+
  Trq_out_max : Product  Inputs=*/
  T_out : Outport
  J_out : Outport  Port=2
  w_up : Outport  Port=3
  sens1 : Outport  Port=4
  sens2 : Outport  Port=5
  sens3 : Outport  Port=6
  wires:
  Constant/1 -> Switch/3
  Product2/1 -> Switch/1  "speed ratio"
  Switch/1 -> Input torque at reference speed = f(speed ratio)/1, Torque ratio = f(speed ratio)/1
  Gain3/1 -> w_up/1  "phys_speed_radps"
  Product5/1 -> MinMax/1, Add1/3
  Gain4/1 -> sens3/1  "TC_tqPumpAct_Nm"
  T_in/1 -> P_in_max/1, Add1/2
  J_in/1 -> Add/1
  w_down/1 -> Gain1/1, Trq_out_max/2, Add3/2, Product2/1
  Gain2/1 -> sens1/1  "TC_tqTurbineAct_Nm"
  Add1/1 -> Product/1
  Add2/1 -> T_out/1, Gain2/1  "phys_torque_Nm"
  Add/1 -> Product/2
  Product4/1 -> Gain4/1, Add1/1, Product3/2  "Input side torque"
  Constant2/1 -> J_out/1  "phys_inertia_kgm2"
  Gain1/1 -> sens2/1  "TC_nTurbineAct_radps"
  Math Function/1 -> Product4/2
  Torque ratio = f(speed ratio)/1 -> Product3/1
  Product1/1 -> Math Function/1
  Constant3/1 -> Add/2
  Product/1 -> Integrator/1
  Input torque at reference speed = f(speed ratio)/1 -> Product4/1
  Integrator/1 -> P_in_max/2, Gain3/1, Add3/1, Product1/1, Switch/2, Product2/2  "TC_nPumpAct_radps"
  Constant4/1 -> Product1/2
  Fcn/1 -> Product5/2
  Add3/1 -> Fcn/1
  T_reqClu/1 -> Product5/1
  MinMax/1 -> Add2/2
  Product3/1 -> Trq_CL_max/1, Add2/1
  P_in_max/1 -> Trq_out_max/1
  Trq_out_max/1 -> Trq_CL_max/2
  Trq_CL_max/1 -> MinMax/2

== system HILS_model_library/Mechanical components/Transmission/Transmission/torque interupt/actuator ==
  T_reqClu : Inport
  T_in : Inport  Port=2
  J_in : Inport  Port=3
  w_down : Inport  Port=4
  Clutch mode : Subsystem
  Demux : Demux  Outputs=3
  Locked clutch : Subsystem
  Memory1 : Memory
  Memory2 : Memory  Orientation=left
  Mux : Mux  Inputs=3
  Mux1 : Mux  Inputs=3
  Slipping clutch : Subsystem  TreatAsAtomicUnit=on
  Switch : Switch  Criteria=u2 ~= 0
  T_out : Outport
  J_out : Outport  Port=2
  w_up : Outport  Port=3
  B_cluLock : Outport  Port=4
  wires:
  Memory1/1 -> Locked clutch/3(w_down), Slipping clutch/3(w_down), Clutch mode/1(w_down)
  Memory2/1 -> Clutch mode/3(w_internal)
  T_in/1 -> Locked clutch/1(T_in), Slipping clutch/1(T_in)
  T_reqClu/1 -> Slipping clutch/4(T_reqClu), Clutch mode/2(T_reqClu)
  J_in/1 -> Locked clutch/2(J_in), Slipping clutch/2(J_in)
  w_down/1 -> Memory1/1
  Slipping clutch/1(T_out) -> Mux1/1
  Slipping clutch/2(J_out) -> Mux1/2
  Slipping clutch/3(w_up) -> Mux1/3
  Locked clutch/1(T_out) -> Mux/1
  Locked clutch/2(J_out) -> Mux/2
  Locked clutch/3(w_up) -> Mux/3
  Mux1/1 -> Switch/1
  Mux/1 -> Switch/3
  Clutch mode/1(B_cluLock) -> B_cluLock/1
  Switch/1 -> Demux/1
  Clutch mode/2(B_cluSlip) -> Slipping clutch/5(B_cluSlip), Switch/2
  Demux/3 -> w_up/1, Memory2/1
  Demux/1 -> T_out/1
  Demux/2 -> J_out/1

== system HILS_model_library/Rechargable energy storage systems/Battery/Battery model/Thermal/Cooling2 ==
  power loss : Inport
  cooling inlet : Inport  Port=2
  Add1 : Sum  Inputs=-+
  Add2 : Sum  Inputs=-+
  Bus Selector : BusSelector  OutputSignals=mass flow [kg/s],temperature [K]
  Gain : Gain  Gain=1/dat.Rth.value
  Gain1 : Gain  Gain=1/dat.cm.value
  Integrator : Integrator  InitialCondition=hilsmdl.init.temp.value
  Mux : Mux  Inputs=3
  Mux1 : Mux  Inputs=2
  calc mean temperature : Fcn  Expr=dat.alpha.value*u(1) + (1-dat.alpha.value)*u(2)
  calc outlet temperature : Fcn  Expr=(u(3)+u(2)*(dat.Rth.value*dat.coolingFluid.c.value*u(1)-dat.alpha.value)) / (1+dat.Rth.value*dat.coolingFluid.c.value*u(1)-dat.alpha.value)
  internal temperature : Outport
  fluid outlet temperature : Outport  Port=2
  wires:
  Mux/1 -> calc outlet temperature/1
  calc outlet temperature/1 -> Mux1/2, fluid outlet temperature/1  "fluid outlet temperature [K]"
  Bus Selector/2 -> Mux1/1, Mux/2  "<temperature [K]>"
  Add1/1 -> Gain/1
  Gain/1 -> Add2/1  "P cooling [W]"
  Add2/1 -> Gain1/1
  Gain1/1 -> Integrator/1
  Integrator/1 -> Mux/3, Add1/2, internal temperature/1  "internal temperature [K]"
  cooling inlet/1 -> Bus Selector/1
  power loss/1 -> Add2/2  "power loss [W]"
  Mux1/1 -> calc mean temperature/1
  calc mean temperature/1 -> Add1/1  "T_mean [K]"
  Bus Selector/1 -> Mux/1  "<mass flow [kg/s]>"

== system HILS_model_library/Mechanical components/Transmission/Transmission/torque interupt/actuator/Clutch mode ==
  w_down : Inport
  T_reqClu : Inport  Port=2
  w_internal : Inport  Port=3
  Abs : Abs
  Add : Sum  Inputs=+-
  Check request condition : RelationalOperator  LogicOutDataTypeMode=boolean  OutDataTypeStr=boolean
  Check request condition2 : RelationalOperator  Operator=<  LogicOutDataTypeMode=boolean  OutDataTypeStr=boolean
  Check speed condition : RelationalOperator  Operator=<  LogicOutDataTypeMode=boolean  OutDataTypeStr=boolean
  Clutch locked S-R Flip-Flop : simulink_extras/Flip Flops/S-R Flip-Flop  SystemSampleTime=-1  initial_condition=0
  Conditions for clutch lock : Logic  AllPortsSameDT=off  OutDataTypeMode=boolean  OutDataTypeStr=boolean
  Speed tolerance [rad/s] : Constant  Value=dat.speedtolerance.value
  maximum torque [Nm] : Constant  Value=dat.maxtorque.value*0.95
  B_cluLock : Outport
  B_cluSlip : Outport  Port=2
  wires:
  w_down/1 -> Add/1
  Add/1 -> Abs/1
  w_internal/1 -> Add/2
  Abs/1 -> Check speed condition/1
  Speed tolerance [rad/s]/1 -> Check speed condition/2
  Check speed condition/1 -> Conditions for clutch lock/1  "speed_ok"
  T_reqClu/1 -> Check request condition/1, Check request condition2/1
  maximum torque [Nm]/1 -> Check request condition/2, Check request condition2/2
  Check request condition/1 -> Conditions for clutch lock/2  "req_ok"
  Conditions for clutch lock/1 -> Clutch locked S-R Flip-Flop/1  "set_lock"
  Check request condition2/1 -> Clutch locked S-R Flip-Flop/2  "req_to_low"
  Clutch locked S-R Flip-Flop/1 -> B_cluLock/1
  Clutch locked S-R Flip-Flop/2 -> B_cluSlip/1

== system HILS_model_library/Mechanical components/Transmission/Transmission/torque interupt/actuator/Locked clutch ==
  T_in : Inport
  J_in : Inport  Port=2
  w_down : Inport  Port=3
  T_out : Outport
  J_out : Outport  Port=2
  w_up : Outport  Port=3
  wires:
  w_down/1 -> w_up/1
  T_in/1 -> T_out/1
  J_in/1 -> J_out/1

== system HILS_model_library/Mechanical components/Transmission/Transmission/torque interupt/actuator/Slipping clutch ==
  T_in : Inport
  J_in : Inport  Port=2
  w_down : Inport  Port=3
  T_reqClu : Inport  Port=4
  B_cluSlip : Inport  Port=5
  " " : Constant  Value=0
  0 when not slipping : Product  Inputs=**
  Add1 : Sum  Inputs=+-
  Add2 : Sum  Inputs=+-
  Calculate input side acc : Product  Inputs=/*
  Fcn : Fcn  Orientation=left  Expr=tanh(dat.tanh.value*u(1))
  Integrate input side speed : Integrator  ExternalReset=rising  InitialConditionSource=external  LimitOutput=on  UpperSaturationLimit=1000  LowerSaturationLimit=0
  Torque direction : Product  Inputs=**
  T_out : Outport
  J_out : Outport  Port=2
  w_up : Outport  Port=3
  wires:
  Fcn/1 -> Torque direction/2
  Calculate input side acc/1 -> 0 when not slipping/1
  0 when not slipping/1 -> Integrate input side speed/1
  T_in/1 -> Add1/1
  B_cluSlip/1 -> Integrate input side speed/2, 0 when not slipping/2
  w_down/1 -> Add2/2, Integrate input side speed/3
  Integrate input side speed/1 -> w_up/1, Add2/1
  Add1/1 -> Calculate input side acc/2  "acc torque"
  T_reqClu/1 -> Torque direction/1
  Torque direction/1 -> Add1/2, T_out/1
  " "/1 -> J_out/1
  J_in/1 -> Calculate input side acc/1
  Add2/1 -> Fcn/1
